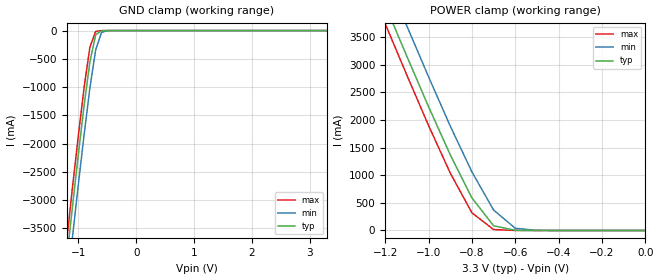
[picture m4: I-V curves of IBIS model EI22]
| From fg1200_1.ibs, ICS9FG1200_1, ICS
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|   Model EI22
[Model]   EI22
Model_type   Input
Polarity   Inverting
Vinl =   0.80V
Vinh =   2.00V
C_comp   3.40pF   2.85pF   3.95pF
[Temperature Range]   27.00   70.00   0.000
[Voltage Range]   3.30V   3.00V   3.70V
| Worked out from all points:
|   GND clamp passes 1 mA (typ) near -0.54 V on its own axis
|   POWER clamp passes 1 mA (typ) near -0.54 V on its own axis
[GND_clamp]
| voltage   I(typ)   I(min)   I(max)
-3.3V     -24.56A    -25.06A    -24.25A
-1.2V     -4.03A     -4.57A     -3.7A
-1.1V     -3.1A      -3.64A     -2.76A
-1V       -2.19A     -2.72A     -1.86A
-900mV    -1.32A     -1.84A     -1A
-800mV    -550mA     -1.01A     -290mA
-700mV    -72.98mA   -340mA     -14.72mA
-600mV    -2.31mA    -32.86mA   -440uA
-500mV    -87.34uA   -1.32mA    -27.68uA
3.3V      71.49pA    1.81uA     53.65pA
[POWER_clamp]
| voltage   I(typ)   I(min)   I(max)
-3.3V     24.62A     25.13A     24.3A
-1.2V     4.08A      4.63A      3.74A
-1.1V     3.15A      3.7A       2.81A
-1V       2.24A      2.78A      1.9A
-900mV    1.37A      1.89A      1.04A
-800mV    590mA      1.06A      320mA
-700mV    85.08mA    370mA      16.78mA
-600mV    2.46mA     39.49mA    260uA
-500mV    53.03uA    1.53mA     3.94uA
0V        71.49pA    320pA      74.53pA
